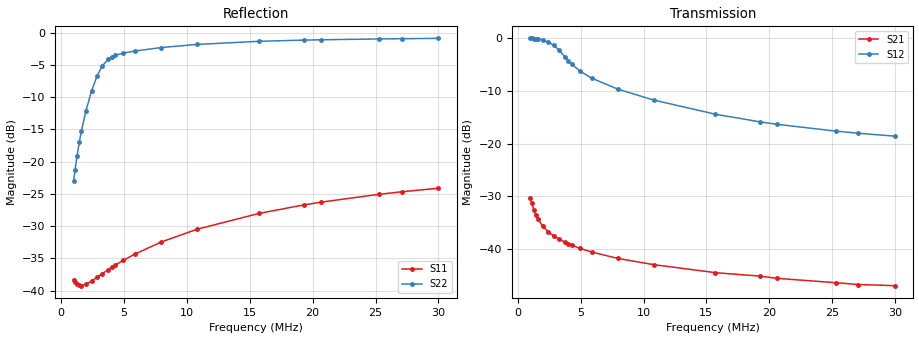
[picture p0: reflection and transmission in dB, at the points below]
! ListType=Log
!!FT240-43 10T CMR
# MHZ S RI R 50
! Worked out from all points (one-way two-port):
!   101 points, 1 MHz to 30 MHz, reference 50 ohm
!   highest |S21| = -30.34 dB at 1 MHz (marker M1); lowest = -46.9 dB at 30 MHz (marker M2)
!   lowest |S11| = -39.2 dB at 1.61 MHz (marker M3), VSWR 1.02, Z = 50 + j1.09 ohm
!   |S11| at or under -10 dB: start of sweep to end of sweep
!   |S22| runs from -23.0 to -0.9 dB; largest |S21 - S12| = 0.99
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1  -0.00106 0.0121  0.00675 -0.0297  0.995 -0.0708  0.00598 0.0707
1.107423  -0.000883 0.0116  0.00676 -0.0264  0.9924 -0.0856  0.00862 0.0854
1.268816  -0.000643 0.0112  0.00696 -0.0227  0.987 -0.1099  0.014 0.1097
1.453729  -0.000472 0.011  0.00722 -0.0196  0.9781 -0.1406  0.0229 0.1403
1.609893  -0.000249 0.0109  0.0074 -0.0177  0.9679 -0.1685  0.0331 0.1681
1.97435  0.000199 0.0112  0.00763 -0.0147  0.9325 -0.2387  0.0684 0.238
2.421316  0.000782 0.0118  0.0077 -0.0124  0.862 -0.3253  0.1387 0.3244
2.87017  0.00136 0.0126  0.00761 -0.0109  0.7585 -0.3958  0.2422 0.3946
3.288459  0.00198 0.0134  0.00747 -0.00993  0.642 -0.4241  0.3585 0.4227
3.767708  0.00265 0.0143  0.00727 -0.00905  0.5241 -0.405  0.4762 0.4035
4.032921  0.00298 0.0148  0.00715 -0.00865  0.476 -0.3828  0.5241 0.3813
4.316802  0.00343 0.0154  0.00704 -0.00828  0.4367 -0.3577  0.5634 0.3562
4.945919  0.0043 0.0166  0.00679 -0.00757  0.3783 -0.3089  0.6217 0.3073
5.862773  0.00568 0.0183  0.00647 -0.00681  0.3285 -0.26  0.6713 0.2582
7.9624  0.00878 0.0221  0.00587 -0.00566  0.2603 -0.2008  0.7393 0.198
10.81396  0.0134 0.0267  0.00529 -0.00476  0.2051 -0.1585  0.7942 0.1542
15.72057  0.0223 0.0327  0.00462 -0.00379  0.1504 -0.1164  0.8486 0.1084
19.27949  0.0294 0.0355  0.00432 -0.00346  0.1288 -0.0963  0.8698 0.0849
20.63659  0.0321 0.0362  0.00415 -0.00326  0.1229 -0.0904  0.8757 0.0777
25.30843  0.0419 0.0368  0.00388 -0.00282  0.1076 -0.0755  0.8907 0.0571
27.08991  0.0456 0.0363  0.00379 -0.00263  0.1033 -0.0714  0.895 0.0505
30  0.0515 0.0347  0.00379 -0.00242  0.0974 -0.0662  0.9008 0.0412
